VERSION 5.7 ;
  NOWIREEXTENSIONATPIN ON ;
  DIVIDERCHAR "/" ;
  BUSBITCHARS "[]" ;
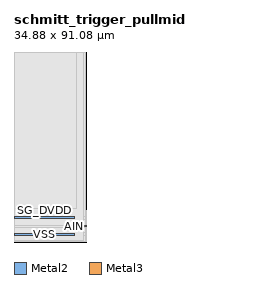
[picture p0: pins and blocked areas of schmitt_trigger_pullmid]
MACRO schmitt_trigger_pullmid
  CLASS BLOCK ;
  FOREIGN schmitt_trigger_pullmid ;
  ORIGIN 0.000 -0.180 ;
  SIZE 34.880 BY 91.080 ;
  PIN SG_DVDD
    ANTENNADIFFAREA 8.599999 ;
    PORT
      LAYER Metal2 ;
        RECT 0.000 11.335 28.900 12.335 ;
    END
  END SG_DVDD
  PIN AIN
    ANTENNAGATEAREA 1.200000 ;
    PORT
      LAYER Metal3 ;
        RECT 27.080 7.515 30.320 8.015 ;
    END
  END AIN
  PIN DOUT
    ANTENNAGATEAREA 0.600000 ;
    ANTENNADIFFAREA 0.680000 ;
    PORT
      LAYER Metal2 ;
        RECT 29.380 7.515 34.665 8.015 ;
    END
  END DOUT
  PIN VSS
    USE GROUND ;
    PORT
      LAYER Metal2 ;
        RECT 0.000 3.445 28.900 4.445 ;
    END
  END VSS
  OBS
      LAYER GatPoly ;
        RECT 0.310 0.310 34.570 15.470 ;
      LAYER Metal1 ;
        RECT 0.000 0.380 34.500 91.260 ;
      LAYER Metal2 ;
        RECT 0.000 12.545 34.300 91.260 ;
        RECT 29.110 11.125 34.300 12.545 ;
        RECT 0.000 8.225 34.300 11.125 ;
        RECT 0.000 7.305 29.170 8.225 ;
        RECT 0.000 4.655 34.300 7.305 ;
        RECT 29.110 3.235 34.300 4.655 ;
        RECT 0.000 0.500 34.300 3.235 ;
      LAYER Metal3 ;
        RECT 0.000 8.225 33.505 91.260 ;
        RECT 0.000 7.305 26.870 8.225 ;
        RECT 30.530 7.305 33.505 8.225 ;
        RECT 0.000 0.680 33.505 7.305 ;
      LAYER Metal4 ;
        RECT 0.000 16.260 30.000 91.260 ;
  END
END schmitt_trigger_pullmid
END LIBRARY

